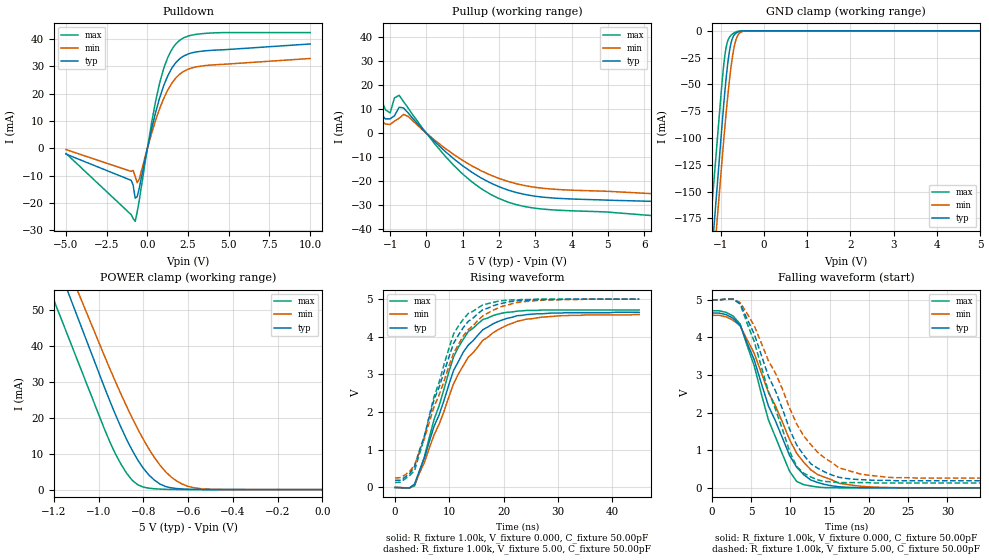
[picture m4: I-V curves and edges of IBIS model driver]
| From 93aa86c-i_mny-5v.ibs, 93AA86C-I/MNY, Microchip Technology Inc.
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|   Model driver
[Model]   driver
Model_type   3-state
Vmeas = 2.5
C_comp   5.00pF   5.00pF   5.00pF
[Temperature Range]   25.00   85.00   -40.00
[Voltage Range]   5.00V   1.80V   5.50V
[Pullup Reference]   5.00V   5.00V   5.00V
[POWER Clamp Reference]   5.00V   5.00V   5.00V
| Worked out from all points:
|   slope of the pulldown table from 0 to 0.75 V, typ, clamps not added: 40.7 ohm
|   slope of the pullup table from 0 to 0.75 V, typ, clamps not added: 70.6 ohm
|   GND clamp passes 1 mA (typ) near -0.59 V on its own axis
|   POWER clamp passes 1 mA (typ) near -0.71 V on its own axis
|   rising waveform, R_fixture 1.00k, V_fixture 0.000, C_fixture 50.00pF: 20-80 % time 7.49ns typ, 8.91ns min, 6.23ns max; typ from 0 V to 4.65 V
|   rising waveform, R_fixture 1.00k, V_fixture 5.00, C_fixture 50.00pF: 20-80 % time 6.77ns typ, 7.56ns min, 5.74ns max; typ from 0.19 V to 5 V
|   falling waveform, R_fixture 1.00k, V_fixture 0.000, C_fixture 50.00pF: 20-80 % time 5ns typ, 5.66ns min, 4.38ns max; typ from 4.65 V to 0 V
|   falling waveform, R_fixture 1.00k, V_fixture 5.00, C_fixture 50.00pF: 20-80 % time 5.29ns typ, 6.5ns min, 4.55ns max; typ from 5 V to 0.19 V
[GND_clamp]
| voltage   I(typ)   I(min)   I(max)
-5V       -2.144A    -2.122A    -2.033A
-1.25V    -233mA     -261.9mA   -188mA
-1.1V     -156.6mA   -187.5mA   -114.2mA
-975mV    -92.86mA   -125.5mA   -52.65mA
-900mV    -56.69mA   -89.9mA    -23mA
-850mV    -36.25mA   -67.89mA   -11.57mA
-775mV    -14.57mA   -39.29mA   -4.945mA
-725mV    -6.897mA   -24.11mA   -2.964mA
-650mV    -2.399mA   -9.125mA   -1.096mA
-550mV    -525.5uA   -1.771mA   -103.4uA
-375mV    -2.846uA   -42.14uA   -47.76nA
5V        10pA       1.104nA    10pA
[POWER_clamp]
| voltage   I(typ)   I(min)   I(max)
-5V       683.9mA    644.3mA    656.2mA
-1.225V   69.32mA    75.05mA    56.7mA
-1.2V     65.25mA    71.28mA    52.73mA
-1.125V   53.04mA    59.97mA    40.82mA
-1.1V     48.97mA    56.2mA     36.85mA
-1.075V   44.9mA     52.43mA    32.88mA
-900mV    17.34mA    26.56mA    7.07mA
-825mV    8.218mA    16.85mA    1.355mA
-750mV    2.602mA    8.865mA    229.3uA
-675mV    483uA      3.462mA    46.1uA
-575mV    57.35uA    525.9uA    1.757uA
0V        10pA       10pA       10pA
[Pulldown]
| voltage   I(typ)   I(min)   I(max)
-5V       -2.134mA   -469.3uA   -1.88mA
-1V       -11.73mA   -8.469mA   -24.28mA
-880mV    -13.41mA   -8.099mA   -25.7mA
-750mV    -18.26mA   -10.32mA   -26.73mA
-630mV    -17.74mA   -12.59mA   -23.4mA
-500mV    -14.57mA   -11.28mA   -19.07mA
250mV     6.874mA    5.336mA    9.108mA
750mV     18.45mA    14.51mA    23.85mA
1.25V     26.53mA    21.32mA    33.22mA
1.75V     31.38mA    25.74mA    38.23mA
3.25V     35.48mA    30.05mA    41.89mA
10V       38.19mA    32.87mA    42.36mA
[Pullup]
| voltage   I(typ)   I(min)   I(max)
-5V       73.95mA    53.31mA    149.2mA
-4.25V    60.75mA    43.71mA    122.2mA
-3.31V    44.25mA    31.71mA    88.42mA
-2.13V    23.35mA    16.51mA    45.67mA
-1.13V    5.957mA    3.835mA    9.823mA
-1V       5.987mA    3.625mA    8.453mA
-880mV    7.277mA    5.055mA    14.71mA
-750mV    10.81mA    6.24mA     15.79mA
-500mV    8.415mA    6.986mA    10.43mA
750mV     -10.63mA   -8.863mA   -13.36mA
2.25V     -23.7mA    -20.11mA   -28.72mA
10V       -29.91mA   -28.22mA   -38.88mA
[Ramp]
| variable   typ   min   max
dV/dt_r   2.79/0.51n   2.75/0.55n   2.83/0.62n
dV/dt_f   2.88/0.54n   2.85/0.60n   2.92/0.49n
R_load = 1.00k
[Rising Waveform]
R_fixture = 1.00k
V_fixture = 0.000
C_fixture = 50.00pF
| time   V(typ)   V(min)   V(max)
0s        730pV      1.59nV     520pV
3.6ns     90.81mV    78.4mV     41.64mV
5.4ns     780mV      660mV      810mV
7.2ns     1.63V      1.4V       1.81V
10.8ns    3.11V      2.76V      3.47V
13.5ns    3.78V      3.46V      4.14V
16.2ns    4.19V      3.91V      4.46V
19.8ns    4.45V      4.25V      4.63V
24.3ns    4.59V      4.47V      4.7V
45ns      4.65V      4.59V      4.71V
[Rising Waveform]
R_fixture = 1.00k
V_fixture = 5.00
C_fixture = 50.00pF
| time   V(typ)   V(min)   V(max)
0s        190mV      250mV      130mV
1.8ns     270mV      330mV      220mV
3.6ns     560mV      590mV      450mV
5.4ns     1.37V      1.29V      1.33V
7.2ns     2.34V      2.15V      2.42V
10.8ns    3.83V      3.57V      4.08V
13.5ns    4.41V      4.19V      4.62V
16.2ns    4.72V      4.56V      4.85V
22.5ns    4.96V      4.91V      4.98V
45ns      5V         5V         5V
[Falling Waveform]
R_fixture = 1.00k
V_fixture = 0.000
C_fixture = 50.00pF
| time   V(typ)   V(min)   V(max)
0s        4.65V      4.59V      4.71V
1.8ns     4.61V      4.55V      4.67V
3.6ns     4.32V      4.31V      4.36V
5.4ns     3.4V       3.57V      3.24V
7.2ns     2.18V      2.54V      1.81V
9.9ns     860mV      1.28V      440mV
10.8ns    550mV      920mV      170mV
13.5ns    140mV      350mV      20.69mV
18ns      11.33mV    66.9mV     210uV
45ns      -2.97nV    480nV      81.8nV
[Falling Waveform]
R_fixture = 1.00k
V_fixture = 5.00
C_fixture = 50.00pF
| time   V(typ)   V(min)   V(max)
0s        5V         5V         5V
3.6ns     4.9V       4.93V      4.89V
5.4ns     4.09V      4.31V      3.89V
7.2ns     2.97V      3.38V      2.57V
9.9ns     1.56V      2.12V      970mV
10.8ns    1.14V      1.7V       570mV
12.6ns    640mV      1.15V      290mV
16.2ns    280mV      530mV      140mV
19.8ns    210mV      340mV      140mV
45ns      190mV      250mV      130mV
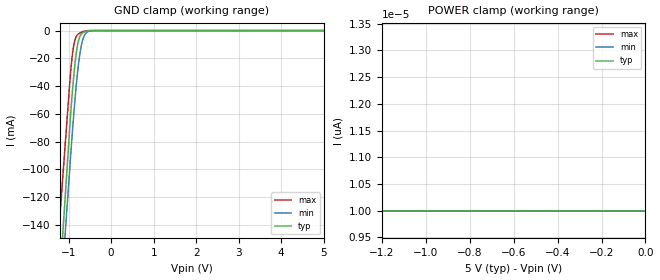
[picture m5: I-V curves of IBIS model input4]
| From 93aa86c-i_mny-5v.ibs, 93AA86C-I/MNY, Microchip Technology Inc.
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|   Model input4
[Model]   input4
Model_type   Input
Vinl = 0.8
Vinh = 2.0
C_comp   5.00pF   5.00pF   5.00pF
[Temperature Range]   25.00   85.00   -40.00
[Voltage Range]   5.00V   1.80V   5.50V
[Pullup Reference]   5.00V   5.00V   5.00V
[POWER Clamp Reference]   5.00V   5.00V   5.00V
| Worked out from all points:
|   GND clamp passes 1 mA (typ) near -0.64 V on its own axis
[GND_clamp]
| voltage   I(typ)   I(min)   I(max)
-5V       -1.955A    -1.858A    -1.708A
-1.25V    -199mA     -220.1mA   -152.1mA
-1.1V     -128.7mA   -154.6mA   -89.91mA
-1V       -81.85mA   -110.9mA   -48.43mA
-925mV    -48.89mA   -78.48mA   -20.75mA
-875mV    -30.97mA   -58.67mA   -9.675mA
-825mV    -17.08mA   -40.61mA   -4.495mA
-775mV    -8.136mA   -25.92mA   -2.532mA
-700mV    -2.414mA   -10.56mA   -1.124mA
-600mV    -588.2uA   -2.062mA   -207.5uA
-425mV    -10.15uA   -74.32uA   -3.271uA
5V        -111.8nA   -87.04nA   -148.1nA
[POWER_clamp]
| voltage   I(typ)   I(min)   I(max)
-5V       10pA       2.324nA    10pA
-4.1V     10pA       1.044nA    10pA
-3.95V    10pA       10pA       10pA
0V        10pA       10pA       10pA
